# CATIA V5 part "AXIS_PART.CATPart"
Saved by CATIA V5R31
Part number: AXIS_PART
Source: Unknown
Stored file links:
  \\solize.local\damia\dept\DDE_Design\10_order\2305701_JAMA_変換検証STEP3_お手本モデル作成\work\03_東洋電装_スイッチ\10_CATIA_V5\AXIS_PART.CATPart

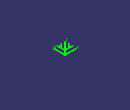
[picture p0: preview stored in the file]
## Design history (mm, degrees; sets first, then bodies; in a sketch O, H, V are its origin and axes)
WSupportSet1
AxisSystem1: origin (0, 0, 0), X (-1, 0, 0), Y (0, -1, 0), Z (0, 0, 1)
Body1 (main body)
